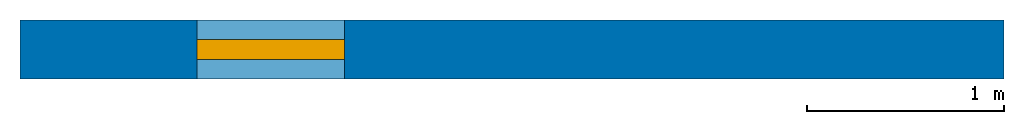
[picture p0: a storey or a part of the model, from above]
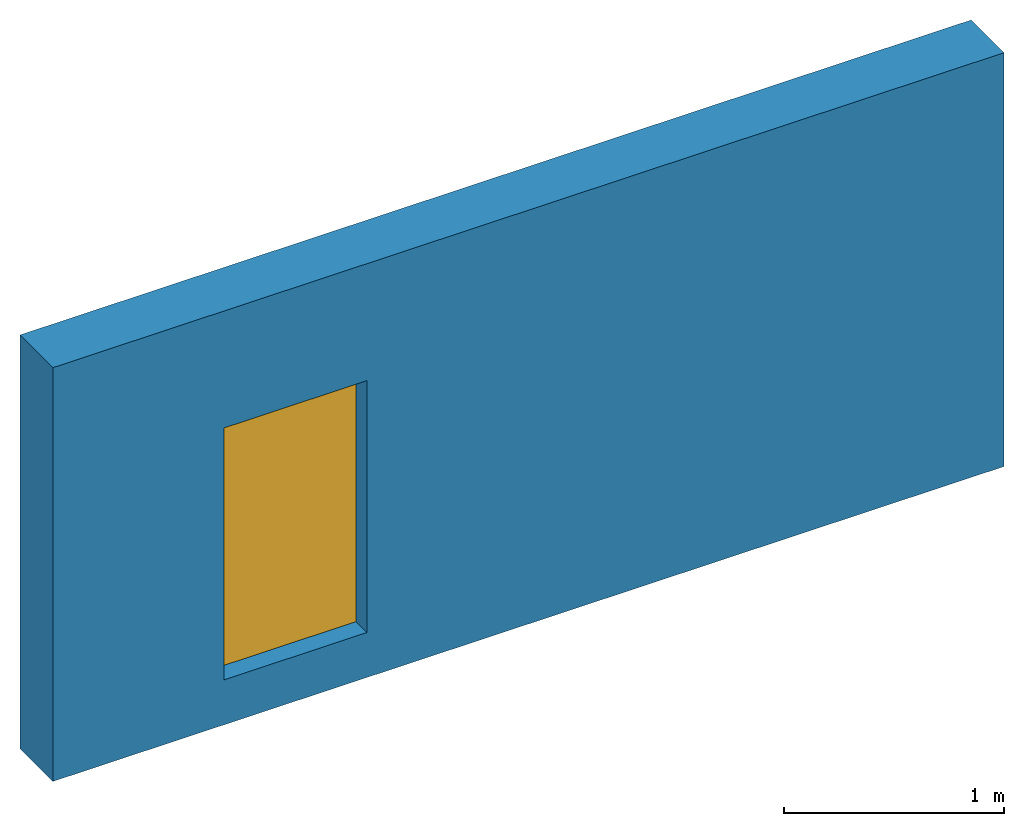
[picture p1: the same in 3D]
Properties of the parts of a building model (IFC2X3)

# File
Description: ViewDefinition [CoordinationView, QuantityTakeOffAddOnView]
File name: example.ifc
Time: 2008-08-01T21:53:56
Author: Architect
Organization: Building Designer Office
Written by: IFC Engine DLL version 1.02 beta
Made in: IFC Engine DLL version 1.02 beta
Authorization: The authorising person

# IfcProject, Default Project
Description: Description of Default Project

# IfcSite, Default Site
Description: Description of Default Site; RefLatitude: 24, 28, 0; RefLongitude: 54, 25, 0

# IfcBuilding, Default Building
Description: Description of Default Building

# IfcBuildingStorey, Default Building Storey
In: Default Building
Description: Description of Default Building Storey; Elevation: 0 m

# IfcOpeningElement, Opening Element xyz
In: Default Building Storey
Description: Description of Opening
BaseQuantities - Depth: 0.3 m; Height: 1.4 m; Width: 0.75 m

# IfcWallStandardCase, Wall xyz
In: Default Building Storey
Description: Description of Wall; Material: Name of the material used for the wall 0.3 m
Pset_WallCommon - Combustible: no; ThermalTransmittance: 0.24; IsExternal: yes; ExtendToStructure: no; LoadBearing: no; Compartmentation: no
BaseQuantities - Width: 0.3 m; Lenght: 5 m; GrossSideArea: 11.5 m2; NetSideArea: 10.45 m2; GrossVolume: 3.45 m3; NetVolume: 3.135 m3; Height: 2.3 m; GrossFootprintArea: 1.5 m2

# IfcWindow, Window xyz
In: Default Building Storey
Description: Description of Window; OverallHeight: 1.4 m; OverallWidth: 0.75 m
Pset_WindowCommon - IsExternal: yes; Infiltration: no; ThermalTransmittance: 0.24; GlazingAresFraction: 0.7; HandicapAccessible: no; FireExit: no; SelfClosing: no; SmokeStop: no
BaseQuantities - Height: 1.4 m; Width: 0.75 m
